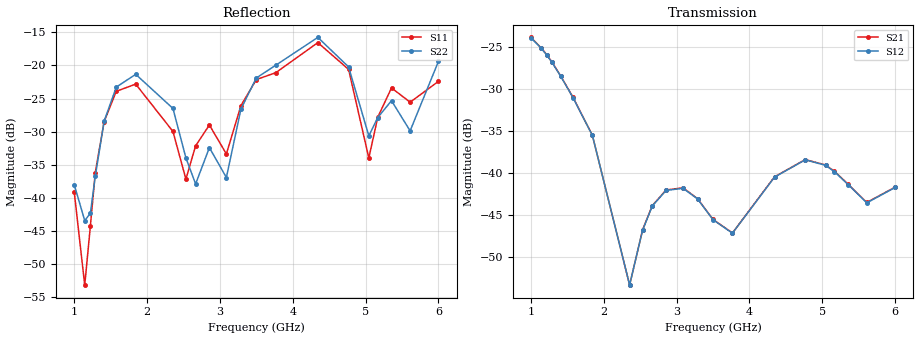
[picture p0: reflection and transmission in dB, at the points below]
!Agilent Technologies,E8364B,MY43040528,A.07.50.67
!Agilent E8364B: A.07.50.67
!Date: Sunday, March 01, 2026 16:13:37
!Correction: S11(Full 2 Port(1,2))
!S21(Full 2 Port(1,2))
!S12(Full 2 Port(1,2))
!S22(Full 2 Port(1,2))
!S2P File: Measurements: S11, S21, S12, S22:
# Hz S  dB  R 50
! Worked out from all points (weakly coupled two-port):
!   451 points, 1 GHz to 6 GHz, reference 50 ohm
!   highest |S21| = -23.83 dB at 1 GHz (marker M1); lowest = -53.3 dB at 2.356 GHz (marker M2)
!   lowest |S11| = -53.2 dB at 1.144 GHz (marker M3), VSWR 1.00, Z = 49.9 + j0.204 ohm
!   |S11| at or under -10 dB: start of sweep to end of sweep
!   |S22| runs from -43.4 to -15.7 dB; largest |S21 - S12| = 0.00029
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1e9  -39.07 33.8  -23.83 152.9  -23.87 153.0  -37.99 -12.7
1.144444e9  -53.15 111.6  -25.11 70.3  -25.15 70.3  -43.41 38.9
1.222222e9  -44.22 -170.8  -25.94 26.0  -25.98 26.0  -42.31 86.6
1.288889e9  -36.18 -164.1  -26.75 -11.8  -26.79 -11.7  -36.75 109.2
1.411111e9  -28.49 176.1  -28.44 -79.8  -28.48 -79.7  -28.41 96.6
1.577778e9  -23.91 139.6  -30.95 -170.0  -30.99 -170.0  -23.28 56.2
1.844444e9  -22.83 88.3  -35.48 47.8  -35.50 47.8  -21.35 -6.6
2.355556e9  -29.97 25.4  -53.31 -148.5  -53.28 -148.3  -26.50 -106.9
2.533333e9  -37.16 53.2  -46.74 169.5  -46.78 169.6  -33.96 -129.9
2.666667e9  -32.13 82.4  -43.85 104.3  -43.90 104.4  -37.89 -83.6
2.855556e9  -29.00 59.3  -41.99 5.5  -42.04 5.6  -32.41 -92.7
3.088889e9  -33.36 66.3  -41.73 -118.7  -41.79 -118.7  -36.92 -82.5
3.288889e9  -26.07 86.1  -43.03 137.0  -43.06 137.2  -26.59 -75.5
3.5e9  -22.14 56.4  -45.49 36.7  -45.53 36.8  -21.90 -119.2
3.766667e9  -21.11 31.4  -47.10 -66.0  -47.13 -66.0  -19.98 -160.9
4.344444e9  -16.57 -40.1  -40.42 22.7  -40.46 22.8  -15.78 99.4
4.766667e9  -20.61 -109.4  -38.37 146.5  -38.40 146.5  -20.24 15.7
5.044444e9  -33.98 -94.1  -39.01 -17.2  -39.05 -17.1  -30.64 13.4
5.166667e9  -27.83 -54.2  -39.76 -90.8  -39.81 -90.8  -27.87 35.2
5.355556e9  -23.40 -77.4  -41.31 151.4  -41.35 151.4  -25.33 10.5
5.611111e9  -25.56 -99.8  -43.47 -22.9  -43.52 -22.9  -29.88 10.6
6e9  -22.41 -90.9  -41.65 59.8  -41.69 59.8  -19.40 -17.0
